VERSION 5.7 ;
  NOWIREEXTENSIONATPIN ON ;
  DIVIDERCHAR "/" ;
  BUSBITCHARS "[]" ;
UNITS
  DATABASE MICRONS 1000 ;
END UNITS

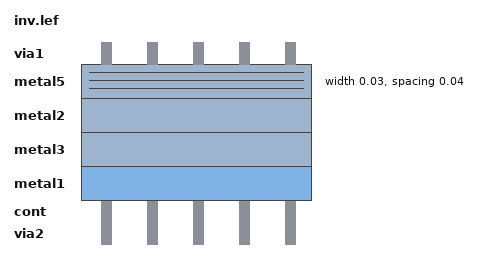
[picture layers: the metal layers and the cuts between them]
LAYER via2
  TYPE CUT ;
END via2

LAYER NWELL
  TYPE MASTERSLICE ;
END NWELL

LAYER cont
  TYPE CUT ;
END cont

LAYER metal1
  TYPE ROUTING ;
END metal1

LAYER metal3
  TYPE ROUTING ;
END metal3

LAYER metal2
  TYPE ROUTING ;
END metal2

LAYER metal5
  TYPE ROUTING ;
  WIDTH 0.030000 ;
  SPACING 0.040000 ;
  DIRECTION HORIZONTAL ;
END metal5

LAYER POLY
  TYPE MASTERSLICE ;
END POLY

LAYER via1
  TYPE CUT ;
END via1

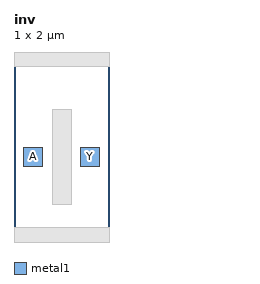
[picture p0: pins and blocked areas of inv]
MACRO inv
  CLASS BLOCK ;
  FOREIGN inv ;
  ORIGIN 0.000 0.000 ;
  SIZE 1.000 BY 2.000 ;
  PIN A
    DIRECTION INPUT ;
    USE SIGNAL ;
    PORT
      LAYER metal1 ;
        RECT 0.100 0.800 0.300 1.000 ;
    END
  END A
  PIN Y
    DIRECTION OUTPUT ;
    USE SIGNAL ;
    PORT
      LAYER metal1 ;
        RECT 0.700 0.800 0.900 1.000 ;
    END
  END Y
  OBS
      LAYER metal1 ;
        RECT 0.000 1.850 1.000 2.000 ;
        RECT 0.400 0.400 0.600 1.400 ;
        RECT 0.000 0.000 1.000 0.150 ;
  END
END inv
END LIBRARY

